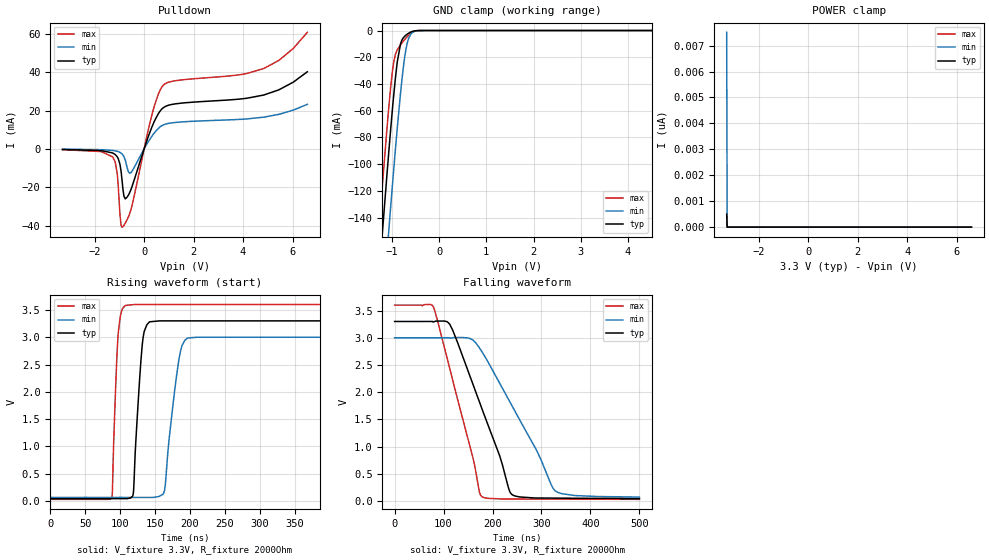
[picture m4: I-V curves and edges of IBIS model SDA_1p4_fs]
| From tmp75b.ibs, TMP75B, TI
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|   Model
[Model]   SDA_1p4_fs
Model_type   I/O_open_drain
Polarity   Non-Inverting
Enable   Active-Low
Vinl = 0.5
Vinh = 1.4
Vmeas = 0.7
Vref = 3.3
Cref = 1pF
Rref = 2000
|   typ   min   max
C_comp   0.767pF   0.704pF   0.863pF
[Voltage Range]   3.3   3   3.6
[Temperature Range]   25   125   -40
[Pullup Reference]   3.3   3   3.6
[Pulldown Reference]   0   0   0
[Power Clamp Reference]   3.3   3   3.6
[GND Clamp Reference]   0   0   0
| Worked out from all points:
|   slope of the pulldown table from 0 to 0.495 V, typ, clamps not added: 30.1 ohm
|   GND clamp passes 1 mA (typ) near -0.59 V on its own axis
|   falling waveform, V_fixture 3.3V, R_fixture 2000Ohm: 20-80 % time 79.8ns typ, 104ns min, 61.5ns max; typ from 3.3 V to 0.042 V
|   rising waveform, V_fixture 3.3V, R_fixture 2000Ohm: 20-80 % time 9.31ns typ, 15.2ns min, 6.31ns max; typ from 0.041 V to 3.3 V
[Pulldown]
|   Voltage   I(typ)   I(min)   I(max)
-3.3V     -298.9uA   -147.6uA   -425.1uA
-1.27V    -2.144mA   -818.8uA   -4.265mA
-1.092V   -4.054mA   -1.248mA   -12.49mA
-973.5mV  -8.328mA   -1.847mA   -34.77mA
-894.3mV  -16.17mA   -2.614mA   -40.84mA
-815.1mV  -24.75mA   -4.104mA   -39.85mA
-636.9mV  -24.13mA   -11.85mA   -35.55mA
-498.3mV  -19.99mA   -11.83mA   -30.05mA
323.4mV   11.68mA    6.808mA    18.15mA
768.9mV   21.43mA    12.48mA    33.13mA
4.838V    28.11mA    16.55mA    41.95mA
6.6V      40.25mA    23.26mA    60.84mA
[GND Clamp]
|   Voltage   I(typ)   I(min)   I(max)
-3.3V     -1.174A    -1.231A    -1.141A
-1.29V    -193.5mA   -253.4mA   -157.8mA
-1.251V   -175.1mA   -235mA     -139.4mA
-1.191V   -147.7mA   -207.5mA   -112.3mA
-1.063V   -90.37mA   -149.1mA   -57.03mA
-963.6mV  -49.9mA    -105.8mA   -24.49mA
-884.4mV  -23.47mA   -73.04mA   -14.42mA
-815.1mV  -9.937mA   -46.83mA   -10.7mA
-755.7mV  -5.477mA   -27.58mA   -7.962mA
-696.3mV  -3.35mA    -13.32mA   -5.458mA
-587.4mV  -990.5uA   -2.271mA   -1.777mA
6.6V      0A         0A         0A
[POWER Clamp]
|   Voltage   I(typ)   I(min)   I(max)
-3.3V     501.8pA    7.511nA    196.3pA
-3.28V    0A         0A         0A
-3.27V    0A         0A         0A
6.6V      0A         0A         0A
[Ramp]
R_load = 2000
|   typ   min   max
dV/dt_r   1.95536/9.28263e-09   1.76165/1.52023e-08   2.14269/6.31036e-09
dV/dt_f   1.95498/7.9695e-08   1.7579/1.03949e-07   2.14266/6.14634e-08
[Falling Waveform]
V_fixture = 3.3V
V_fixture_min = 3V
V_fixture_max = 3.6V
R_fixture = 2000Ohm
C_fixture = 0F
|   Time   V(typ)   V(min)   V(max)
0s        3.3V       3V         3.6V
79.31ns   3.292V     3V         3.567V
112.7ns   3.247V     3V         2.431V
151.1ns   2.363V     2.995V     1.098V
173.2ns   1.821V     2.814V     163.4mV
177.6ns   1.713V     2.753V     81.41mV
214.7ns   824.3mV    2.162V     37.23mV
236.3ns   150.1mV    1.806V     34.16mV
327.1ns   51.23mV    192.5mV    32.35mV
500ns     41.7mV     70.17mV    28.9mV
[Rising Waveform]
V_fixture = 3.3V
V_fixture_min = 3V
V_fixture_max = 3.6V
R_fixture = 2000Ohm
C_fixture = 0F
|   Time   V(typ)   V(min)   V(max)
0s        41.07mV    63.9mV     28.85mV
88.04ns   41.07mV    63.89mV    58.57mV
97.06ns   41.07mV    63.88mV    3.018V
107.3ns   41.07mV    63.88mV    3.58V
118.9ns   132.6mV    63.88mV    3.597V
131.5ns   2.82V      63.88mV    3.6V
142ns     3.28V      63.87mV    3.6V
163.6ns   3.3V       184.2mV    3.6V
196.4ns   3.3V       2.983V     3.6V
500ns     3.3V       3V         3.6V
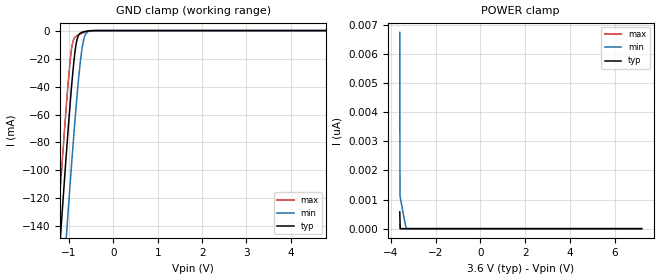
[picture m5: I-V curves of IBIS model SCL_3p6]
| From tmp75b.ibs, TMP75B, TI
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|   Model
[Model]   SCL_3p6
Model_type   Input
Vinl = 0.9
Vinh = 2.1
|   typ   min   max
C_comp   0.318pF   0.315pF   0.322pF
[Voltage Range]   3.6   3.59   3.61
[Temperature Range]   25   125   -40
[Power Clamp Reference]   3.6   3.59   3.61
[GND Clamp Reference]   0   0   0
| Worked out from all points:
|   GND clamp passes 1 mA (typ) near -0.68 V on its own axis
[GND Clamp]
|   Voltage   I(typ)   I(min)   I(max)
-3.6V     -1.323A    -1.379A    -1.29A
-1.278V   -187mA     -247.1mA   -151mA
-1.192V   -147mA     -207mA     -111mA
-1.181V   -142mA     -202mA     -106.1mA
-1.094V   -103mA     -162.6mA   -67.72mA
-1.03V    -74.89mA   -133.6mA   -40.99mA
-943.2mV  -40.14mA   -96.06mA   -13.06mA
-835.2mV  -8.818mA   -52.55mA   -3.88mA
-716.4mV  -1.368mA   -15.12mA   -2.02mA
-619.2mV  -484.9uA   -2.217mA   -869uA
-457.2mV  -25.1uA    -65.22uA   -36.59uA
7.2V      0A         0A         0A
[POWER Clamp]
|   Voltage   I(typ)   I(min)   I(max)
-3.6V     577.6pA    6.747nA    137.7pA
-3.589V   288.8pA    1.129nA    68.85pA
-3.578V   0A         1.082nA    0A
-3.438V   0A         493.2pA    0A
-3.308V   0A         0A         0A
7.2V      0A         0A         0A
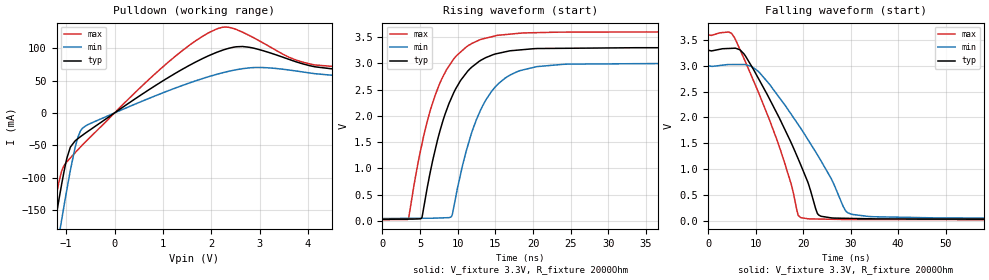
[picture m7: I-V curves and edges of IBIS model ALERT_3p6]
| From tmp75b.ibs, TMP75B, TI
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|   Model
[Model]   ALERT_3p6
Model_type   Open_drain
Polarity   Non-Inverting
Vmeas = 1.65
Vref = 3.3
Cref = 1pF
Rref = 2000
|   typ   min   max
C_comp   0.817pF   0.754pF   0.967pF
[Voltage Range]   3.3   3   3.6
[Temperature Range]   25   125   -40
[Pullup Reference]   3.3   3   3.6
[Pulldown Reference]   0   -0   -0
[Power Clamp Reference]   3.3   3   3.6
[GND Clamp Reference]   0   0   0
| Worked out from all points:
|   slope of the pulldown table from 0 to 0.495 V, typ, clamps not added: 19.6 ohm
|   falling waveform, V_fixture 3.3V, R_fixture 2000Ohm: 20-80 % time 10ns typ, 12ns min, 8.65ns max; typ from 3.3 V to 0.031 V
|   rising waveform, V_fixture 3.3V, R_fixture 2000Ohm: 20-80 % time 4.24ns typ, 4.23ns min, 4.27ns max; typ from 0.031 V to 3.3 V
[Pulldown]
|   Voltage   I(typ)   I(min)   I(max)
-3.3V     -1.175A    -1.231A    -1.142A
-1.459V   -275mA     -333.7mA   -240.8mA
-1.241V   -173.9mA   -231.7mA   -142.1mA
-1.092V   -109.3mA   -164.3mA   -89.49mA
-914.1mV  -52.76mA   -88.75mA   -69.46mA
-755.7mV  -39.53mA   -36.94mA   -56.63mA
-656.7mV  -33.99mA   -23.09mA   -48.87mA
1.125V    55.26mA    34.68mA    79.3mA
2.145V    94.47mA    60.25mA    130.5mA
2.788V    101.4mA    69.57mA    119.5mA
4.145V    71.23mA    60.62mA    74.07mA
6.6V      72.05mA    56.38mA    86.57mA
[Ramp]
R_load = 2000
|   typ   min   max
dV/dt_r   1.96115/4.2298e-09   1.77274/4.2157e-09   2.14582/4.26473e-09
dV/dt_f   1.96115/9.97767e-09   1.77274/1.19874e-08   2.14582/8.64283e-09
[Falling Waveform]
V_fixture = 3.3V
V_fixture_min = 3V
V_fixture_max = 3.6V
R_fixture = 2000Ohm
C_fixture = 0F
|   Time   V(typ)   V(min)   V(max)
0s        3.3V       3V         3.6V
5.497ns   3.339V     3.024V     3.551V
9.132ns   2.992V     2.987V     2.8V
14.64ns   2.052V     2.428V     1.527V
18.95ns   1.202V     1.865V     112.4mV
20.94ns   761.8mV    1.583V     41.53mV
23.3ns    111.6mV    1.233V     36.14mV
29.02ns   50.01mV    186.7mV    27.71mV
34.79ns   39.89mV    80.68mV    26.92mV
500ns     31.41mV    45.42mV    23.64mV
[Rising Waveform]
V_fixture = 3.3V
V_fixture_min = 3V
V_fixture_max = 3.6V
R_fixture = 2000Ohm
C_fixture = 0F
|   Time   V(typ)   V(min)   V(max)
0s        31.41mV    45.42mV    23.64mV
3.466ns   34.32mV    48.68mV    38.22mV
5.229ns   56.28mV    50.33mV    1.447V
7.3ns     1.53V      55.01mV    2.502V
9.132ns   2.331V     77.81mV    3.014V
11.13ns   2.817V     1.333V     3.314V
13.08ns   3.061V     2.126V     3.457V
15.43ns   3.195V     2.618V     3.538V
18.56ns   3.262V     2.874V     3.58V
500ns     3.3V       3V         3.6V
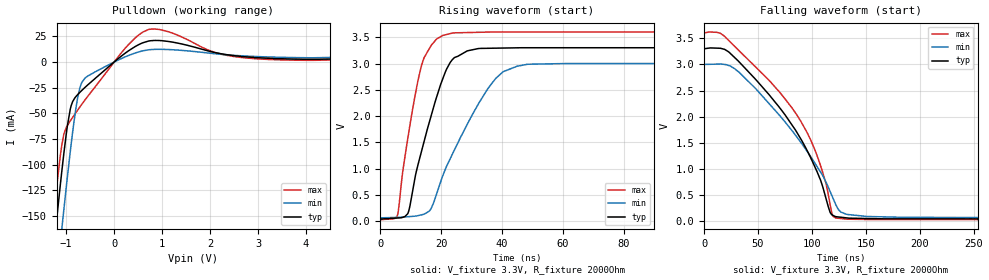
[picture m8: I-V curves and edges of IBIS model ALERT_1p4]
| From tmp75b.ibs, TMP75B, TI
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|   Model
[Model]   ALERT_1p4
Model_type   Open_drain
Polarity   Non-Inverting
Vmeas = 1.65
Vref = 3.3
Cref = 1pF
Rref = 2000
|   typ   min   max
C_comp   0.817pF   0.754pF   0.967pF
[Voltage Range]   3.3   3   3.6
[Temperature Range]   25   125   -40
[Pullup Reference]   3.3   3   3.6
[Pulldown Reference]   0   0   0
[Power Clamp Reference]   3.3   3   3.6
[GND Clamp Reference]   0   0   0
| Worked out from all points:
|   slope of the pulldown table from 0 to 0.495 V, typ, clamps not added: 30 ohm
|   falling waveform, V_fixture 3.3V, R_fixture 2000Ohm: 20-80 % time 58.9ns typ, 61.9ns min, 61.8ns max; typ from 3.3 V to 0.041 V
|   rising waveform, V_fixture 3.3V, R_fixture 2000Ohm: 20-80 % time 9.14ns typ, 14.9ns min, 6.26ns max; typ from 0.041 V to 3.3 V
[Pulldown]
|   Voltage   I(typ)   I(min)   I(max)
-3.3V     -1.175A    -1.231A    -1.142A
-1.27V    -186.4mA   -245mA     -152.9mA
-1.221V   -163.8mA   -222.1mA   -131.1mA
-1.092V   -107.3mA   -163.6mA   -81.61mA
-1.043V   -87.16mA   -141.7mA   -69.57mA
-904.2mV  -44.13mA   -83.5mA    -56.62mA
-765.6mV  -32mA      -36.27mA   -47.22mA
-666.6mV  -27.33mA   -19.32mA   -40.7mA
244.2mV   9.089mA    5.299mA    14.12mA
709.5mV   20.34mA    11.85mA    31.53mA
2.66V     5.422mA    6.069mA    4.415mA
6.6V      4.646mA    6.312mA    4.088mA
[Ramp]
R_load = 2000
|   typ   min   max
dV/dt_r   1.95536/9.12444e-09   1.76173/1.48605e-08   2.14269/6.24654e-09
dV/dt_f   1.95536/5.88506e-08   1.76171/6.17186e-08   2.14269/6.145e-08
[Falling Waveform]
V_fixture = 3.3V
V_fixture_min = 3V
V_fixture_max = 3.6V
R_fixture = 2000Ohm
C_fixture = 0F
|   Time   V(typ)   V(min)   V(max)
0s        3.3V       3V         3.6V
15.11ns   3.309V     3.008V     3.596V
28.63ns   3.127V     2.914V     3.341V
81.17ns   1.852V     1.743V     2.178V
103ns     1.027V     1.102V     1.352V
112.8ns   452.2mV    757.8mV    738.6mV
116.8ns   173mV      571.1mV    326.3mV
121.9ns   88.87mV    328.5mV    64.24mV
151.3ns   51.14mV    90.2mV     32.98mV
500ns     41.06mV    63.81mV    28.85mV
[Rising Waveform]
V_fixture = 3.3V
V_fixture_min = 3V
V_fixture_max = 3.6V
R_fixture = 2000Ohm
C_fixture = 0F
|   Time   V(typ)   V(min)   V(max)
0s        41.06mV    63.78mV    28.85mV
5.671ns   60.86mV    72.53mV    118.9mV
9.069ns   149.9mV    85.36mV    1.586V
14.44ns   1.527V     135mV      3.116V
16.79ns   2.021V     252.2mV    3.349V
19.85ns   2.605V     752.4mV    3.512V
23.71ns   3.076V     1.278V     3.579V
37.95ns   3.292V     2.717V     3.6V
48.7ns    3.3V       2.986V     3.6V
500ns     3.3V       3V         3.6V
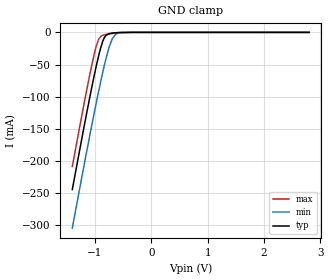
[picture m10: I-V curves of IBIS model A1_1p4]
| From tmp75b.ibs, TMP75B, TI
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|   Model
[Model]   A1_1p4
Model_type   Input
Vinl = 0.5
Vinh = 1.3
|   typ   min   max
C_comp   0.319pF   0.314pF   0.326pF
[Voltage Range]   1.4   1.39   1.41
[Temperature Range]   25   125   -40
[Power Clamp Reference]   1.4   1.39   1.41
[GND Clamp Reference]   0   0   0
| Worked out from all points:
|   GND clamp passes 1 mA (typ) near -0.68 V on its own axis
[GND Clamp]
|   Voltage   I(typ)   I(min)   I(max)
-1.4V     -244.5mA   -304.5mA   -208.6mA
-1.161V   -132.8mA   -192.7mA   -96.94mA
-1.035V   -77.01mA   -135.8mA   -42.95mA
-975.8mV  -52.72mA   -110mA     -21.86mA
-929.6mV  -35.18mA   -90.33mA   -10.36mA
-858.2mV  -13.47mA   -61.35mA   -4.448mA
-828.8mV  -7.788mA   -50.17mA   -3.769mA
-744.8mV  -1.881mA   -22.37mA   -2.431mA
-690.2mV  -1.07mA    -9.814mA   -1.697mA
-627.2mV  -552.2uA   -2.668mA   -972.5uA
-350mV    -14.71uA   -14.54uA   -26.47uA
2.8V      0A         0A         0A
[POWER Clamp]
|   Voltage   I(typ)   I(min)   I(max)
-1.4V     0A         0A         0A
-1.396V   0A         0A         0A
292.6mV   0A         0A         0A
2.8V      0A         0A         0A
